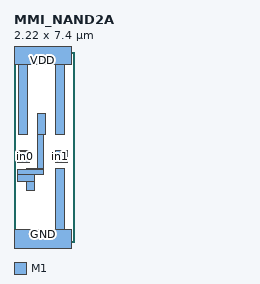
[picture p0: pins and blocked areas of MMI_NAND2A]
MACRO MMI_NAND2A
	CLASS CORE ;
	FOREIGN MMI_NAND2A 0 0 ;
	SIZE 2.22 BY 7.4 ;
	SYMMETRY X Y ;
	SITE CORE1 ;
	PIN out
		DIRECTION output ;
		USE SIGNAL ;
		PORT
			LAYER M1 ;
			RECT 0.9 4.18 1.24 5.02 ;
			LAYER M1 ;
			RECT 0.9 2.845 1.13 4.18 ;
			LAYER M1 ;
			RECT 0.47 2.815 1.13 2.845 ;
			LAYER M1 ;
			RECT 0.145 2.615 1.13 2.815 ;
			LAYER M1 ;
			RECT 0.145 2.365 0.81 2.615 ;
			LAYER M1 ;
			RECT 0.47 2.005 0.81 2.365 ;
		END
		AntennaDiffArea 0.9384 ;
	END out
	PIN in1
		DIRECTION input ;
		USE SIGNAL ;
		PORT
			LAYER M1 ;
			RECT 1.625 3.5 2.075 3.555 ;
			LAYER M1 ;
			RECT 1.51 3.16 2.075 3.5 ;
			LAYER M1 ;
			RECT 1.625 3.105 2.075 3.16 ;
		END
		AntennaGateArea 0.3312 ;
	END in1
	PIN GND
		DIRECTION inout ;
		USE GROUND ;
		PORT
			LAYER M1 ;
			RECT 1.62 0.5 1.96 2.845 ;
			LAYER M1 ;
			RECT 0 -0.5 2.22 0.5 ;
		END
	END GND
	PIN VDD
		DIRECTION inout ;
		USE POWER ;
		PORT
			LAYER M1 ;
			RECT 0 6.9 2.22 7.9 ;
			LAYER M1 ;
			RECT 0.18 4.18 0.52 6.9 ;
			LAYER M1 ;
			RECT 1.62 4.18 1.96 6.9 ;
		END
	END VDD
	PIN in0
		DIRECTION input ;
		USE SIGNAL ;
		PORT
			LAYER M1 ;
			RECT 0.145 3.51 0.61 3.555 ;
			LAYER M1 ;
			RECT 0.145 3.17 0.655 3.51 ;
			LAYER M1 ;
			RECT 0.145 3.105 0.595 3.17 ;
		END
		AntennaGateArea 0.3312 ;
	END in0
	OBS
	END
END MMI_NAND2A
